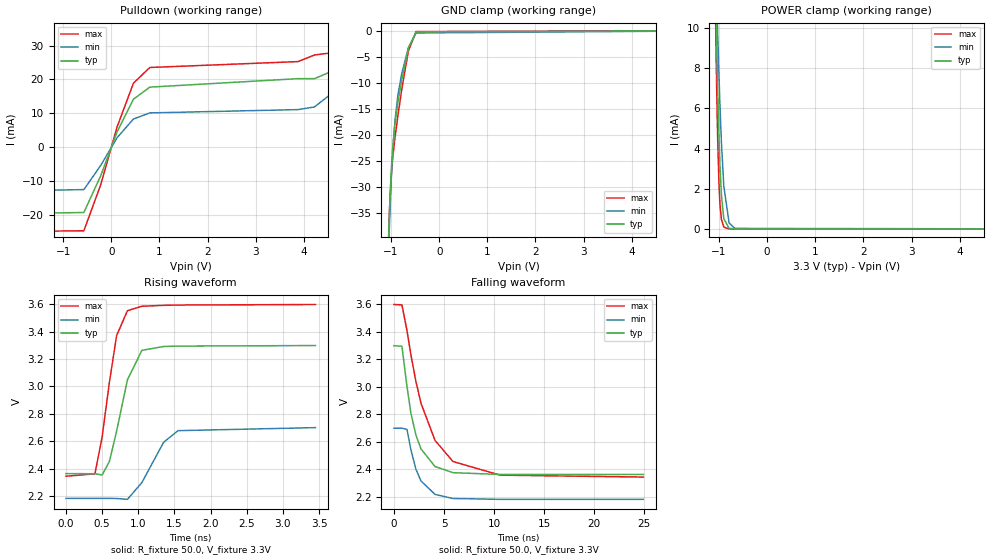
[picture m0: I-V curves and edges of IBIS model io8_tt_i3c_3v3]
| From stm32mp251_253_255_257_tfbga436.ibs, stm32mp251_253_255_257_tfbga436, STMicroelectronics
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[Model]   io8_tt_i3c_3v3
Model_type I/O_open_drain
Polarity   Non-Inverting
Enable   Active-Low
| CAP_THRESHOLD on pad IOTT is "UDTCAPC" :
| Rising=30.0% of vddiov33m   Falling=70.0% of vddiov33m
| C_comp min and max val. don't necessarily correlate with the min and max pvt
| but are the smallest and greatest pad capacitance found.
| var   typ   min   max
C_comp   1.28835pF  1.05072pF  2.25290pF
|C_comp_pulldown   1.28835pF  1.05072pF  2.25290pF
Vinl = 810.0mV
Vinh = 2.52V
Vmeas = 1.65V   | Reference voltage for timing measurements
Cref  = 50.0pF   | Timing specification test load capacitance value
Rref  = 100.0MOhm   | Timing specification test load resistance value
Vref  = 1.65V   | Timing specification test load voltage
[Model Spec]
| TIME_THRESHOLD on pin ZIV08M is "CMOS" :
| Rising=50.0% of vddv08m   Falling=50.0% of vddv08m
Vinl 1.08570V 868.70000mV 1.21270V
Vinh 1.55630V 1.26330V 1.71030V
| variable   typ   min   max
[Temperature Range] 25.0 125.0 -40.0
| variable   typ   min   max
[Voltage Range] 3.3V 2.7V 3.6V
| variable   typ   min   max
[POWER Clamp Reference] 3.3V 2.7V 3.6V
| variable   typ   min   max
[GND Clamp Reference] 0V 0V 0V
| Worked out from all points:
|   slope of the pulldown table from 0 to 0.495 V, typ, clamps not added: 34.1 ohm
|   GND clamp passes 1 mA (typ) near -0.55 V on its own axis
|   POWER clamp passes 1 mA (typ) near -0.93 V on its own axis
|   rising waveform, R_fixture 50.0, V_fixture 3.3V: 20-80 % time 236ps typ, 319ps min, 203ps max; typ from 2.36 V to 3.3 V
|   falling waveform, R_fixture 50.0, V_fixture 3.3V: 20-80 % time 1.56ns typ, 1.42ns min, 2.79ns max; typ from 3.3 V to 2.36 V
[POWER Clamp]
-3.3V     1.352A     318.4mA    1.997A
-1.07V    12.07mA    13.62mA    10.38mA
-1.06V    10.79mA    12.67mA    8.742mA
-1.05V    9.57mA     11.75mA    7.25mA
-1.03V    7.34mA     9.996mA    4.745mA
-1V       4.587mA    7.593mA    2.212mA
-980mV    3.182mA    6.169mA    1.235mA
-950mV    1.703mA    4.334mA    479uA
-900mV    514.7uA    2.139mA    90.77uA
-790mV    28.73uA    299.8uA    2.71uA
-670mV    1.277uA    27.48uA    387.3nA
6.6V      0A         0A         0A
[GND Clamp]
-3.3V     -3.764A    -3.734A    -3.781A
-1.05V    -39.76mA   -42.44mA   -39.2mA
-1.04V    -36.65mA   -39.24mA   -36.3mA
-1.03V    -33.91mA   -36.36mA   -33.82mA
-1V       -27.43mA   -29.21mA   -28.35mA
-970mV    -22.87mA   -23.78mA   -24.78mA
-920mV    -17.9mA    -17.36mA   -20.6mA
-860mV    -13.88mA   -12.47mA   -16.46mA
-780mV    -9.533mA   -8.281mA   -11.38mA
-640mV    -3.394mA   -3.284mA   -3.897mA
-480mV    -254.3uA   -469.3uA   -191.8uA
6.6V      212.3nA    5.122uA    219.5nA
| variable   typ   min   max
[Pullup Reference] 3.3V 2.7V 3.6V
| variable   typ   min   max
[Pulldown Reference] 0V 0V 0V
[Pulldown]
-3.3V     -19.95mA   -13.29mA   -25.2mA
-570mV    -19.4mA    -12.62mA   -24.8mA
-220mV    -8.542mA   -5.471mA   -11.2mA
120mV     4.438mA    2.727mA    5.906mA
460mV     14.14mA    8.27mA     18.88mA
800mV     17.71mA    10.08mA    23.52mA
3.88V     20.22mA    11.06mA    25.27mA
4.22V     20.22mA    11.84mA    27.23mA
4.56V     22.27mA    15.63mA    27.84mA
4.9V      31.19mA    28.07mA    34.84mA
5.24V     59.66mA    64.92mA    58.18mA
6.6V      396.6mA    415.2mA    364.6mA
[Ramp]
dV/dt_r 561.48305mV/234.27297ps 310.44879mV/318.0262ps 752.65379mV/201.23077ps
dV/dt_f 562.26768mV/1.56379ns 311.02646mV/1.41772ns 753.53466mV/2.78572ns
R_load = 50.0
| Removed startup time: 0s 0s 0s  .
| Removed end time: 3.45ns.
[Rising Waveform]
R_fixture   = 50.0
V_fixture   = 3.3V
V_fixture_min = 2.7V
V_fixture_max = 3.6V
0s        2.363V     2.182V     2.344V
400ps     2.362V     2.182V     2.361V
500ps     2.353V     2.182V     2.632V
600ps     2.451V     2.182V     3.029V
700ps     2.673V     2.181V     3.372V
850ps     3.049V     2.175V     3.554V
1.05ns    3.264V     2.298V     3.586V
1.35ns    3.292V     2.592V     3.593V
1.55ns    3.295V     2.677V     3.595V
3.45ns    3.299V     2.699V     3.599V
| Removed startup time: 0s 0s 0s  .
| Removed end time: 24.9ns.
[Falling Waveform]
R_fixture   = 50.0
V_fixture   = 3.3V
V_fixture_min = 2.7V
V_fixture_max = 3.6V
0s        3.3V       2.7V       3.6V
800ps     3.296V     2.7V       3.597V
1.3ns     3.006V     2.691V     3.412V
1.7ns     2.807V     2.542V     3.233V
2.2ns     2.649V     2.4V       3.038V
2.7ns     2.549V     2.316V     2.882V
4.1ns     2.421V     2.218V     2.611V
5.9ns     2.376V     2.188V     2.457V
10.6ns    2.363V     2.182V     2.358V
24.9ns    2.363V     2.182V     2.344V
